VERSION 5.8 ;
BUSBITCHARS "[]" ;
DIVIDERCHAR "/" ;

SITE  CoreSite4
    CLASS       CORE ;
    SYMMETRY    Y ;
    SIZE        0.48 BY 15.12 ;
END  CoreSite4

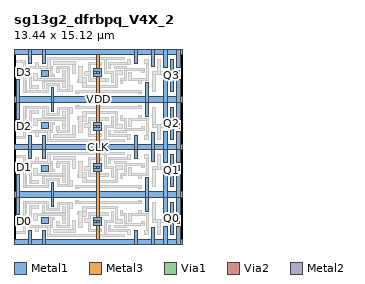
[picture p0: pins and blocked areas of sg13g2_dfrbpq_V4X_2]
MACRO sg13g2_dfrbpq_V4X_2
  CLASS CORE ;
  ORIGIN 0 0 ;
  FOREIGN sg13g2_dfrbpq_V4X_2 0 0 ;
  SIZE 13.440 BY 15.120 ;
  SYMMETRY X Y ;
  SITE CoreSite4 ;
  PIN D0
    DIRECTION INPUT ;
    USE SIGNAL ;
    ANTENNAMODEL OXIDE1 ;
    ANTENNAGATEAREA 0.1092 LAYER Metal1 ;
    PORT
      LAYER Metal1 ;
        RECT 0.255 1.375 0.610 1.855 ;
    END
  END D0
  PIN Q0
    DIRECTION OUTPUT ;
    USE SIGNAL ;
    ANTENNADIFFAREA 0.7161 LAYER Metal1 ;
    PORT
      LAYER Metal1 ;
        RECT 12.440 1.505 13.150 1.845 ;
        RECT 12.440 0.595 12.700 3.160 ;
    END
  END Q0
  PIN D1
    DIRECTION INPUT ;
    USE SIGNAL ;
    ANTENNAMODEL OXIDE1 ;
    ANTENNAGATEAREA 0.1092 LAYER Metal1 ;
    PORT
      LAYER Metal1 ;
        RECT 0.255 5.705 0.610 6.185 ;
    END
  END D1
  PIN Q1
    DIRECTION OUTPUT ;
    USE SIGNAL ;
    ANTENNADIFFAREA 0.7161 LAYER Metal1 ;
    PORT
      LAYER Metal1 ;
        RECT 12.440 4.400 12.700 6.965 ;
        RECT 12.440 5.715 13.150 6.055 ;
    END
  END Q1
  PIN D2
    DIRECTION INPUT ;
    USE SIGNAL ;
    ANTENNAMODEL OXIDE1 ;
    ANTENNAGATEAREA 0.1092 LAYER Metal1 ;
    PORT
      LAYER Metal1 ;
        RECT 0.255 8.935 0.610 9.415 ;
    END
  END D2
  PIN Q2
    DIRECTION OUTPUT ;
    USE SIGNAL ;
    ANTENNADIFFAREA 0.7161 LAYER Metal1 ;
    PORT
      LAYER Metal1 ;
        RECT 12.440 9.065 13.150 9.405 ;
        RECT 12.440 8.155 12.700 10.720 ;
    END
  END Q2
  PIN D3
    DIRECTION INPUT ;
    USE SIGNAL ;
    ANTENNAMODEL OXIDE1 ;
    ANTENNAGATEAREA 0.1092 LAYER Metal1 ;
    PORT
      LAYER Metal1 ;
        RECT 0.255 13.265 0.610 13.745 ;
    END
  END D3
  PIN Q3
    DIRECTION OUTPUT ;
    USE SIGNAL ;
    ANTENNADIFFAREA 0.7161 LAYER Metal1 ;
    PORT
      LAYER Metal1 ;
        RECT 12.440 11.960 12.700 14.525 ;
        RECT 12.440 13.275 13.150 13.615 ;
    END
  END Q3
  PIN VDD
    DIRECTION INOUT ;
    USE POWER ;
    SHAPE ABUTMENT ;
    NETEXPR "VDD VDD!" ;
    PORT
      LAYER Metal1 ;
        RECT 11.930 2.190 12.190 4.000 ;
        RECT 0.215 2.215 0.470 4.000 ;
        RECT 12.955 2.220 13.215 4.000 ;
        RECT 10.450 2.460 10.710 4.000 ;
        RECT 2.945 2.860 3.115 4.000 ;
        RECT 0.000 3.560 13.440 4.000 ;
        RECT 2.945 3.560 3.115 4.700 ;
        RECT 10.450 3.560 10.710 5.100 ;
        RECT 12.955 3.560 13.215 5.340 ;
        RECT 0.215 3.560 0.470 5.345 ;
        RECT 11.930 3.560 12.190 5.370 ;
    END
    PORT
      LAYER Metal1 ;
        RECT 11.930 9.750 12.190 11.560 ;
        RECT 0.215 9.775 0.470 11.560 ;
        RECT 12.955 9.780 13.215 11.560 ;
        RECT 10.450 10.020 10.710 11.560 ;
        RECT 2.945 10.420 3.115 11.560 ;
        RECT 0.000 11.120 13.440 11.560 ;
        RECT 2.945 11.120 3.115 12.260 ;
        RECT 10.450 11.120 10.710 12.660 ;
        RECT 12.955 11.120 13.215 12.900 ;
        RECT 0.215 11.120 0.470 12.905 ;
        RECT 11.930 11.120 12.190 12.930 ;
    END
  END VDD
  PIN VSS
    DIRECTION INOUT ;
    USE GROUND ;
    SHAPE ABUTMENT ;
    NETEXPR "VSS VSS!" ;
    PORT
      LAYER Metal1 ;
        RECT 0.000 -0.220 13.440 0.220 ;
        RECT 9.560 -0.220 9.820 0.885 ;
        RECT 1.140 -0.220 1.400 0.885 ;
        RECT 2.235 -0.220 2.495 0.915 ;
        RECT 10.925 -0.220 11.160 1.190 ;
        RECT 12.960 -0.220 13.215 1.200 ;
        RECT 11.935 -0.220 12.200 1.200 ;
    END
    PORT
      LAYER Metal1 ;
        RECT 12.960 6.360 13.215 7.780 ;
        RECT 11.935 6.360 12.200 7.780 ;
        RECT 10.925 6.370 11.160 7.780 ;
        RECT 2.235 6.645 2.495 7.780 ;
        RECT 9.560 6.675 9.820 7.780 ;
        RECT 1.140 6.675 1.400 7.780 ;
        RECT 0.000 7.340 13.440 7.780 ;
        RECT 9.560 7.340 9.820 8.445 ;
        RECT 1.140 7.340 1.400 8.445 ;
        RECT 2.235 7.340 2.495 8.475 ;
        RECT 10.925 7.340 11.160 8.750 ;
        RECT 12.960 7.340 13.215 8.760 ;
        RECT 11.935 7.340 12.200 8.760 ;
    END
    PORT
      LAYER Metal1 ;
        RECT 12.960 13.920 13.215 15.340 ;
        RECT 11.935 13.920 12.200 15.340 ;
        RECT 10.925 13.930 11.160 15.340 ;
        RECT 2.235 14.205 2.495 15.340 ;
        RECT 9.560 14.235 9.820 15.340 ;
        RECT 1.140 14.235 1.400 15.340 ;
        RECT 0.000 14.900 13.440 15.340 ;
    END
  END VSS
  PIN CLK
    DIRECTION INPUT ;
    USE SIGNAL ;
    ANTENNAMODEL OXIDE1 ;
    ANTENNAGATEAREA 0.2418 LAYER Metal1 ;
    PORT
      LAYER Metal1 ;
        RECT 6.365 1.335 6.990 1.935 ;
        RECT 6.365 5.625 6.990 6.225 ;
        RECT 6.365 8.895 6.990 9.495 ;
        RECT 6.365 13.185 6.990 13.785 ;
      LAYER Metal3 ;
        RECT 6.580 0.200 6.780 14.920 ;
      LAYER Via1 ;
        RECT 6.365 1.540 6.555 1.730 ;
      LAYER Via2 ;
        RECT 6.580 1.540 6.770 1.730 ;
      LAYER Metal2 ;
        RECT 6.360 1.535 6.775 1.735 ;
      LAYER Via1 ;
        RECT 6.365 5.830 6.555 6.020 ;
      LAYER Via2 ;
        RECT 6.580 5.830 6.770 6.020 ;
      LAYER Metal2 ;
        RECT 6.360 5.825 6.775 6.025 ;
      LAYER Via1 ;
        RECT 6.365 9.100 6.555 9.290 ;
      LAYER Via2 ;
        RECT 6.580 9.100 6.770 9.290 ;
      LAYER Metal2 ;
        RECT 6.360 9.095 6.775 9.295 ;
      LAYER Via1 ;
        RECT 6.365 13.390 6.555 13.580 ;
      LAYER Via2 ;
        RECT 6.580 13.390 6.770 13.580 ;
      LAYER Metal2 ;
        RECT 6.360 13.385 6.775 13.585 ;
    END
  END CLK
  PIN RESET_B
    DIRECTION INPUT ;
    USE SIGNAL ;
    ANTENNAPARTIALMETALAREA 0.905 LAYER Metal1 ;
    ANTENNAMODEL OXIDE1 ;
    ANTENNAGATEAREA 0.3276 LAYER Metal1 ;
    ANTENNAMAXAREACAR 2.762515 LAYER Metal1 ;
    PORT
      LAYER Metal1 ;
        RECT 2.200 1.510 2.750 1.965 ;
    END
    PORT
      LAYER Metal1 ;
        RECT 2.200 5.595 2.750 6.050 ;
    END
    PORT
      LAYER Metal1 ;
        RECT 2.200 9.070 2.750 9.525 ;
    END
    PORT
      LAYER Metal1 ;
        RECT 2.200 13.155 2.750 13.610 ;
    END
  END RESET_B
  OBS
    LAYER Metal1 ;
      RECT 10.990 1.555 11.250 3.105 ;
      RECT 10.990 1.555 11.920 1.795 ;
      RECT 11.410 1.540 11.920 1.795 ;
      RECT 11.410 0.590 11.670 1.795 ;
      RECT 9.910 2.100 10.170 2.495 ;
      RECT 9.130 2.100 10.730 2.260 ;
      RECT 10.570 0.625 10.730 2.260 ;
      RECT 9.130 1.655 9.385 2.260 ;
      RECT 10.380 0.625 10.730 0.885 ;
      RECT 8.455 2.125 8.660 2.500 ;
      RECT 8.455 2.125 8.950 2.295 ;
      RECT 8.790 1.145 8.950 2.295 ;
      RECT 10.165 1.275 10.390 1.665 ;
      RECT 8.790 1.275 10.390 1.465 ;
      RECT 7.960 1.145 8.970 1.315 ;
      RECT 9.910 3.025 10.180 3.285 ;
      RECT 4.855 3.025 5.115 3.285 ;
      RECT 4.855 3.075 10.180 3.235 ;
      RECT 7.510 0.805 7.680 1.310 ;
      RECT 7.510 0.805 9.310 0.965 ;
      RECT 9.050 0.625 9.310 0.965 ;
      RECT 1.200 2.640 1.940 2.900 ;
      RECT 1.200 1.170 1.360 2.900 ;
      RECT 7.745 1.555 7.935 2.450 ;
      RECT 2.935 1.755 3.215 1.965 ;
      RECT 2.935 1.170 3.095 1.965 ;
      RECT 7.170 1.555 7.935 1.725 ;
      RECT 7.170 0.440 7.330 1.725 ;
      RECT 1.200 1.170 3.095 1.330 ;
      RECT 2.705 0.440 2.875 1.330 ;
      RECT 1.720 0.815 1.980 1.330 ;
      RECT 8.540 0.440 8.800 0.625 ;
      RECT 2.705 0.440 8.800 0.605 ;
      RECT 5.425 2.630 8.275 2.790 ;
      RECT 8.115 1.510 8.275 2.790 ;
      RECT 5.425 2.060 5.785 2.790 ;
      RECT 5.020 2.150 5.785 2.410 ;
      RECT 5.155 2.060 5.785 2.410 ;
      RECT 5.155 1.135 5.415 2.410 ;
      RECT 8.115 1.510 8.600 1.770 ;
      RECT 5.965 2.145 7.525 2.370 ;
      RECT 7.265 2.075 7.525 2.370 ;
      RECT 5.965 0.855 6.125 2.370 ;
      RECT 5.650 1.540 6.125 1.870 ;
      RECT 6.755 0.810 6.990 1.070 ;
      RECT 5.965 0.855 6.990 1.025 ;
      RECT 4.630 1.440 4.895 1.700 ;
      RECT 4.685 1.300 4.895 1.700 ;
      RECT 4.685 0.785 4.865 1.700 ;
      RECT 3.165 0.785 4.865 0.960 ;
      RECT 0.790 3.080 2.765 3.240 ;
      RECT 2.605 2.520 2.765 3.240 ;
      RECT 3.455 2.985 4.625 3.145 ;
      RECT 4.290 2.685 4.625 3.145 ;
      RECT 0.790 2.240 0.980 3.240 ;
      RECT 3.455 2.520 3.615 3.145 ;
      RECT 4.290 1.170 4.450 3.145 ;
      RECT 2.605 2.520 3.615 2.680 ;
      RECT 0.720 2.240 0.980 2.520 ;
      RECT 0.790 0.645 0.950 3.240 ;
      RECT 3.385 1.225 3.645 1.640 ;
      RECT 3.465 1.170 4.450 1.330 ;
      RECT 0.210 0.645 0.950 0.840 ;
      RECT 2.245 2.145 2.425 2.900 ;
      RECT 3.890 1.510 4.075 2.805 ;
      RECT 2.245 2.145 4.075 2.315 ;
      RECT 1.585 2.145 4.075 2.305 ;
      RECT 1.585 1.705 1.845 2.305 ;
      RECT 3.890 1.510 4.110 1.810 ;
      RECT 10.990 4.455 11.250 6.005 ;
      RECT 10.990 5.765 11.920 6.005 ;
      RECT 11.410 5.765 11.920 6.020 ;
      RECT 11.410 5.765 11.670 6.970 ;
      RECT 9.910 5.065 10.170 5.460 ;
      RECT 9.130 5.300 10.730 5.460 ;
      RECT 10.570 5.300 10.730 6.935 ;
      RECT 9.130 5.300 9.385 5.905 ;
      RECT 10.380 6.675 10.730 6.935 ;
      RECT 8.455 5.060 8.660 5.435 ;
      RECT 8.455 5.265 8.950 5.435 ;
      RECT 8.790 5.265 8.950 6.415 ;
      RECT 10.165 5.895 10.390 6.285 ;
      RECT 8.790 6.095 10.390 6.285 ;
      RECT 7.960 6.245 8.970 6.415 ;
      RECT 9.910 4.275 10.180 4.535 ;
      RECT 4.855 4.275 5.115 4.535 ;
      RECT 4.855 4.325 10.180 4.485 ;
      RECT 7.510 6.250 7.680 6.755 ;
      RECT 7.510 6.595 9.310 6.755 ;
      RECT 9.050 6.595 9.310 6.935 ;
      RECT 1.200 4.660 1.940 4.920 ;
      RECT 1.200 4.660 1.360 6.390 ;
      RECT 7.745 5.110 7.935 6.005 ;
      RECT 2.935 5.595 3.215 5.805 ;
      RECT 2.935 5.595 3.095 6.390 ;
      RECT 7.170 5.835 7.935 6.005 ;
      RECT 7.170 5.835 7.330 7.120 ;
      RECT 1.200 6.230 3.095 6.390 ;
      RECT 2.705 6.230 2.875 7.120 ;
      RECT 1.720 6.230 1.980 6.745 ;
      RECT 8.540 6.935 8.800 7.120 ;
      RECT 2.705 6.955 8.800 7.120 ;
      RECT 5.425 4.770 8.275 4.930 ;
      RECT 8.115 4.770 8.275 6.050 ;
      RECT 5.425 4.770 5.785 5.500 ;
      RECT 5.020 5.150 5.785 5.410 ;
      RECT 5.155 5.150 5.785 5.500 ;
      RECT 5.155 5.150 5.415 6.425 ;
      RECT 8.115 5.790 8.600 6.050 ;
      RECT 5.965 5.190 7.525 5.415 ;
      RECT 7.265 5.190 7.525 5.485 ;
      RECT 5.965 5.190 6.125 6.705 ;
      RECT 5.650 5.690 6.125 6.020 ;
      RECT 6.755 6.490 6.990 6.750 ;
      RECT 5.965 6.535 6.990 6.705 ;
      RECT 4.630 5.860 4.895 6.120 ;
      RECT 4.685 5.860 4.895 6.260 ;
      RECT 4.685 5.860 4.865 6.775 ;
      RECT 3.165 6.600 4.865 6.775 ;
      RECT 0.790 4.320 2.765 4.480 ;
      RECT 2.605 4.320 2.765 5.040 ;
      RECT 3.455 4.415 4.625 4.575 ;
      RECT 4.290 4.415 4.625 4.875 ;
      RECT 0.790 4.320 0.980 5.320 ;
      RECT 3.455 4.415 3.615 5.040 ;
      RECT 4.290 4.415 4.450 6.390 ;
      RECT 2.605 4.880 3.615 5.040 ;
      RECT 0.720 5.040 0.980 5.320 ;
      RECT 0.790 4.320 0.950 6.915 ;
      RECT 3.385 5.920 3.645 6.335 ;
      RECT 3.465 6.230 4.450 6.390 ;
      RECT 0.210 6.720 0.950 6.915 ;
      RECT 2.245 4.660 2.425 5.415 ;
      RECT 3.890 4.755 4.075 6.050 ;
      RECT 2.245 5.245 4.075 5.415 ;
      RECT 1.585 5.255 4.075 5.415 ;
      RECT 1.585 5.255 1.845 5.855 ;
      RECT 3.890 5.750 4.110 6.050 ;
      RECT 10.990 9.115 11.250 10.665 ;
      RECT 10.990 9.115 11.920 9.355 ;
      RECT 11.410 9.100 11.920 9.355 ;
      RECT 11.410 8.150 11.670 9.355 ;
      RECT 9.910 9.660 10.170 10.055 ;
      RECT 9.130 9.660 10.730 9.820 ;
      RECT 10.570 8.185 10.730 9.820 ;
      RECT 9.130 9.215 9.385 9.820 ;
      RECT 10.380 8.185 10.730 8.445 ;
      RECT 8.455 9.685 8.660 10.060 ;
      RECT 8.455 9.685 8.950 9.855 ;
      RECT 8.790 8.705 8.950 9.855 ;
      RECT 10.165 8.835 10.390 9.225 ;
      RECT 8.790 8.835 10.390 9.025 ;
      RECT 7.960 8.705 8.970 8.875 ;
      RECT 9.910 10.585 10.180 10.845 ;
      RECT 4.855 10.585 5.115 10.845 ;
      RECT 4.855 10.635 10.180 10.795 ;
      RECT 7.510 8.365 7.680 8.870 ;
      RECT 7.510 8.365 9.310 8.525 ;
      RECT 9.050 8.185 9.310 8.525 ;
      RECT 1.200 10.200 1.940 10.460 ;
      RECT 1.200 8.730 1.360 10.460 ;
      RECT 7.745 9.115 7.935 10.010 ;
      RECT 2.935 9.315 3.215 9.525 ;
      RECT 2.935 8.730 3.095 9.525 ;
      RECT 7.170 9.115 7.935 9.285 ;
      RECT 7.170 8.000 7.330 9.285 ;
      RECT 1.200 8.730 3.095 8.890 ;
      RECT 2.705 8.000 2.875 8.890 ;
      RECT 1.720 8.375 1.980 8.890 ;
      RECT 8.540 8.000 8.800 8.185 ;
      RECT 2.705 8.000 8.800 8.165 ;
      RECT 5.425 10.190 8.275 10.350 ;
      RECT 8.115 9.070 8.275 10.350 ;
      RECT 5.425 9.620 5.785 10.350 ;
      RECT 5.020 9.710 5.785 9.970 ;
      RECT 5.155 9.620 5.785 9.970 ;
      RECT 5.155 8.695 5.415 9.970 ;
      RECT 8.115 9.070 8.600 9.330 ;
      RECT 5.965 9.705 7.525 9.930 ;
      RECT 7.265 9.635 7.525 9.930 ;
      RECT 5.965 8.415 6.125 9.930 ;
      RECT 5.650 9.100 6.125 9.430 ;
      RECT 6.755 8.370 6.990 8.630 ;
      RECT 5.965 8.415 6.990 8.585 ;
      RECT 4.630 9.000 4.895 9.260 ;
      RECT 4.685 8.860 4.895 9.260 ;
      RECT 4.685 8.345 4.865 9.260 ;
      RECT 3.165 8.345 4.865 8.520 ;
      RECT 0.790 10.640 2.765 10.800 ;
      RECT 2.605 10.080 2.765 10.800 ;
      RECT 3.455 10.545 4.625 10.705 ;
      RECT 4.290 10.245 4.625 10.705 ;
      RECT 0.790 9.800 0.980 10.800 ;
      RECT 3.455 10.080 3.615 10.705 ;
      RECT 4.290 8.730 4.450 10.705 ;
      RECT 2.605 10.080 3.615 10.240 ;
      RECT 0.720 9.800 0.980 10.080 ;
      RECT 0.790 8.205 0.950 10.800 ;
      RECT 3.385 8.785 3.645 9.200 ;
      RECT 3.465 8.730 4.450 8.890 ;
      RECT 0.210 8.205 0.950 8.400 ;
      RECT 2.245 9.705 2.425 10.460 ;
      RECT 3.890 9.070 4.075 10.365 ;
      RECT 2.245 9.705 4.075 9.875 ;
      RECT 1.585 9.705 4.075 9.865 ;
      RECT 1.585 9.265 1.845 9.865 ;
      RECT 3.890 9.070 4.110 9.370 ;
      RECT 10.990 12.015 11.250 13.565 ;
      RECT 10.990 13.325 11.920 13.565 ;
      RECT 11.410 13.325 11.920 13.580 ;
      RECT 11.410 13.325 11.670 14.530 ;
      RECT 9.910 12.625 10.170 13.020 ;
      RECT 9.130 12.860 10.730 13.020 ;
      RECT 10.570 12.860 10.730 14.495 ;
      RECT 9.130 12.860 9.385 13.465 ;
      RECT 10.380 14.235 10.730 14.495 ;
      RECT 8.455 12.620 8.660 12.995 ;
      RECT 8.455 12.825 8.950 12.995 ;
      RECT 8.790 12.825 8.950 13.975 ;
      RECT 10.165 13.455 10.390 13.845 ;
      RECT 8.790 13.655 10.390 13.845 ;
      RECT 7.960 13.805 8.970 13.975 ;
      RECT 9.910 11.835 10.180 12.095 ;
      RECT 4.855 11.835 5.115 12.095 ;
      RECT 4.855 11.885 10.180 12.045 ;
      RECT 7.510 13.810 7.680 14.315 ;
      RECT 7.510 14.155 9.310 14.315 ;
      RECT 9.050 14.155 9.310 14.495 ;
      RECT 1.200 12.220 1.940 12.480 ;
      RECT 1.200 12.220 1.360 13.950 ;
      RECT 7.745 12.670 7.935 13.565 ;
      RECT 2.935 13.155 3.215 13.365 ;
      RECT 2.935 13.155 3.095 13.950 ;
      RECT 7.170 13.395 7.935 13.565 ;
      RECT 7.170 13.395 7.330 14.680 ;
      RECT 1.200 13.790 3.095 13.950 ;
      RECT 2.705 13.790 2.875 14.680 ;
      RECT 1.720 13.790 1.980 14.305 ;
      RECT 8.540 14.495 8.800 14.680 ;
      RECT 2.705 14.515 8.800 14.680 ;
      RECT 5.425 12.330 8.275 12.490 ;
      RECT 8.115 12.330 8.275 13.610 ;
      RECT 5.425 12.330 5.785 13.060 ;
      RECT 5.020 12.710 5.785 12.970 ;
      RECT 5.155 12.710 5.785 13.060 ;
      RECT 5.155 12.710 5.415 13.985 ;
      RECT 8.115 13.350 8.600 13.610 ;
      RECT 5.965 12.750 7.525 12.975 ;
      RECT 7.265 12.750 7.525 13.045 ;
      RECT 5.965 12.750 6.125 14.265 ;
      RECT 5.650 13.250 6.125 13.580 ;
      RECT 6.755 14.050 6.990 14.310 ;
      RECT 5.965 14.095 6.990 14.265 ;
      RECT 4.630 13.420 4.895 13.680 ;
      RECT 4.685 13.420 4.895 13.820 ;
      RECT 4.685 13.420 4.865 14.335 ;
      RECT 3.165 14.160 4.865 14.335 ;
      RECT 0.790 11.880 2.765 12.040 ;
      RECT 2.605 11.880 2.765 12.600 ;
      RECT 3.455 11.975 4.625 12.135 ;
      RECT 4.290 11.975 4.625 12.435 ;
      RECT 0.790 11.880 0.980 12.880 ;
      RECT 3.455 11.975 3.615 12.600 ;
      RECT 4.290 11.975 4.450 13.950 ;
      RECT 2.605 12.440 3.615 12.600 ;
      RECT 0.720 12.600 0.980 12.880 ;
      RECT 0.790 11.880 0.950 14.475 ;
      RECT 3.385 13.480 3.645 13.895 ;
      RECT 3.465 13.790 4.450 13.950 ;
      RECT 0.210 14.280 0.950 14.475 ;
      RECT 2.245 12.220 2.425 12.975 ;
      RECT 3.890 12.315 4.075 13.610 ;
      RECT 2.245 12.805 4.075 12.975 ;
      RECT 1.585 12.815 4.075 12.975 ;
      RECT 1.585 12.815 1.845 13.415 ;
      RECT 3.890 13.310 4.110 13.610 ;
  END
END sg13g2_dfrbpq_V4X_2

END LIBRARY
